VERSION 5.8 ;
BUSBITCHARS "[]" ;
DIVIDERCHAR "/" ;
UNITS
    DATABASE MICRONS 1000 ;
END UNITS

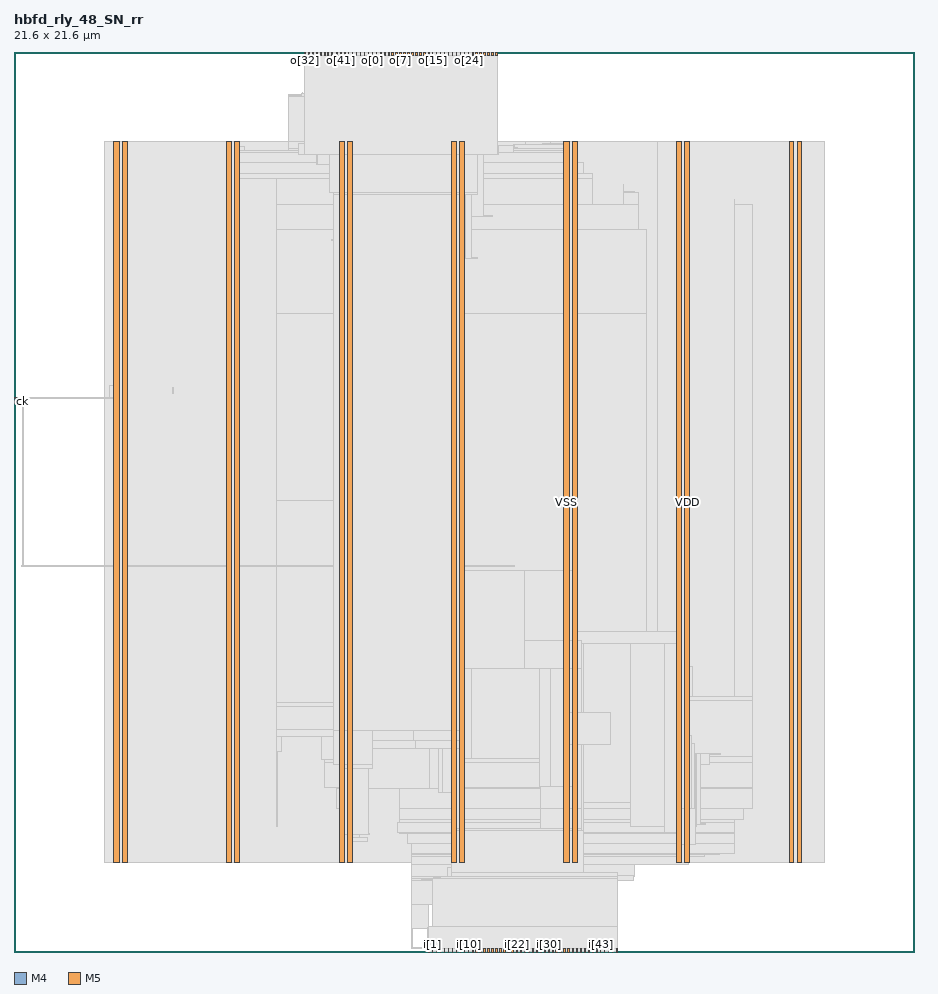
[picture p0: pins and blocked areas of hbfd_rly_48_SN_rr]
MACRO hbfd_rly_48_SN_rr
  FOREIGN hbfd_rly_48_SN_rr 0 0 ;
  CLASS BLOCK ;
  SIZE 21.6 BY 21.6 ;
  PIN ck
    DIRECTION INPUT ;
    USE SIGNAL ;
    PORT
      LAYER M4 ;
        RECT  0 13.2 0.084 13.224 ;
    END
  END ck
  PIN i[0]
    DIRECTION INPUT ;
    USE SIGNAL ;
    PORT
      LAYER M5 ;
        RECT  9.936 0 9.96 0.084 ;
    END
  END i[0]
  PIN i[10]
    DIRECTION INPUT ;
    USE SIGNAL ;
    PORT
      LAYER M5 ;
        RECT  10.896 0 10.92 0.084 ;
    END
  END i[10]
  PIN i[11]
    DIRECTION INPUT ;
    USE SIGNAL ;
    PORT
      LAYER M5 ;
        RECT  10.992 0 11.016 0.084 ;
    END
  END i[11]
  PIN i[12]
    DIRECTION INPUT ;
    USE SIGNAL ;
    PORT
      LAYER M5 ;
        RECT  11.088 0 11.112 0.084 ;
    END
  END i[12]
  PIN i[13]
    DIRECTION INPUT ;
    USE SIGNAL ;
    PORT
      LAYER M5 ;
        RECT  11.184 0 11.208 0.084 ;
    END
  END i[13]
  PIN i[14]
    DIRECTION INPUT ;
    USE SIGNAL ;
    PORT
      LAYER M5 ;
        RECT  11.28 0 11.304 0.084 ;
    END
  END i[14]
  PIN i[15]
    DIRECTION INPUT ;
    USE SIGNAL ;
    PORT
      LAYER M5 ;
        RECT  11.376 0 11.4 0.084 ;
    END
  END i[15]
  PIN i[16]
    DIRECTION INPUT ;
    USE SIGNAL ;
    PORT
      LAYER M5 ;
        RECT  11.472 0 11.496 0.084 ;
    END
  END i[16]
  PIN i[17]
    DIRECTION INPUT ;
    USE SIGNAL ;
    PORT
      LAYER M5 ;
        RECT  11.568 0 11.592 0.084 ;
    END
  END i[17]
  PIN i[18]
    DIRECTION INPUT ;
    USE SIGNAL ;
    PORT
      LAYER M5 ;
        RECT  11.664 0 11.688 0.084 ;
    END
  END i[18]
  PIN i[19]
    DIRECTION INPUT ;
    USE SIGNAL ;
    PORT
      LAYER M5 ;
        RECT  11.76 0 11.784 0.084 ;
    END
  END i[19]
  PIN i[1]
    DIRECTION INPUT ;
    USE SIGNAL ;
    PORT
      LAYER M5 ;
        RECT  10.032 0 10.056 0.084 ;
    END
  END i[1]
  PIN i[20]
    DIRECTION INPUT ;
    USE SIGNAL ;
    PORT
      LAYER M5 ;
        RECT  11.856 0 11.88 0.084 ;
    END
  END i[20]
  PIN i[21]
    DIRECTION INPUT ;
    USE SIGNAL ;
    PORT
      LAYER M5 ;
        RECT  11.952 0 11.976 0.084 ;
    END
  END i[21]
  PIN i[22]
    DIRECTION INPUT ;
    USE SIGNAL ;
    PORT
      LAYER M5 ;
        RECT  12.048 0 12.072 0.084 ;
    END
  END i[22]
  PIN i[23]
    DIRECTION INPUT ;
    USE SIGNAL ;
    PORT
      LAYER M5 ;
        RECT  12.144 0 12.168 0.084 ;
    END
  END i[23]
  PIN i[24]
    DIRECTION INPUT ;
    USE SIGNAL ;
    PORT
      LAYER M5 ;
        RECT  12.24 0 12.264 0.084 ;
    END
  END i[24]
  PIN i[25]
    DIRECTION INPUT ;
    USE SIGNAL ;
    PORT
      LAYER M5 ;
        RECT  12.336 0 12.36 0.084 ;
    END
  END i[25]
  PIN i[26]
    DIRECTION INPUT ;
    USE SIGNAL ;
    PORT
      LAYER M5 ;
        RECT  12.432 0 12.456 0.084 ;
    END
  END i[26]
  PIN i[27]
    DIRECTION INPUT ;
    USE SIGNAL ;
    PORT
      LAYER M5 ;
        RECT  12.528 0 12.552 0.084 ;
    END
  END i[27]
  PIN i[28]
    DIRECTION INPUT ;
    USE SIGNAL ;
    PORT
      LAYER M5 ;
        RECT  12.624 0 12.648 0.084 ;
    END
  END i[28]
  PIN i[29]
    DIRECTION INPUT ;
    USE SIGNAL ;
    PORT
      LAYER M5 ;
        RECT  12.72 0 12.744 0.084 ;
    END
  END i[29]
  PIN i[2]
    DIRECTION INPUT ;
    USE SIGNAL ;
    PORT
      LAYER M5 ;
        RECT  10.128 0 10.152 0.084 ;
    END
  END i[2]
  PIN i[30]
    DIRECTION INPUT ;
    USE SIGNAL ;
    PORT
      LAYER M5 ;
        RECT  12.816 0 12.84 0.084 ;
    END
  END i[30]
  PIN i[31]
    DIRECTION INPUT ;
    USE SIGNAL ;
    PORT
      LAYER M5 ;
        RECT  12.912 0 12.936 0.084 ;
    END
  END i[31]
  PIN i[32]
    DIRECTION INPUT ;
    USE SIGNAL ;
    PORT
      LAYER M5 ;
        RECT  13.008 0 13.032 0.084 ;
    END
  END i[32]
  PIN i[33]
    DIRECTION INPUT ;
    USE SIGNAL ;
    PORT
      LAYER M5 ;
        RECT  13.104 0 13.128 0.084 ;
    END
  END i[33]
  PIN i[34]
    DIRECTION INPUT ;
    USE SIGNAL ;
    PORT
      LAYER M5 ;
        RECT  13.2 0 13.224 0.084 ;
    END
  END i[34]
  PIN i[35]
    DIRECTION INPUT ;
    USE SIGNAL ;
    PORT
      LAYER M5 ;
        RECT  13.296 0 13.32 0.084 ;
    END
  END i[35]
  PIN i[36]
    DIRECTION INPUT ;
    USE SIGNAL ;
    PORT
      LAYER M5 ;
        RECT  13.392 0 13.416 0.084 ;
    END
  END i[36]
  PIN i[37]
    DIRECTION INPUT ;
    USE SIGNAL ;
    PORT
      LAYER M5 ;
        RECT  13.488 0 13.512 0.084 ;
    END
  END i[37]
  PIN i[38]
    DIRECTION INPUT ;
    USE SIGNAL ;
    PORT
      LAYER M5 ;
        RECT  13.584 0 13.608 0.084 ;
    END
  END i[38]
  PIN i[39]
    DIRECTION INPUT ;
    USE SIGNAL ;
    PORT
      LAYER M5 ;
        RECT  13.68 0 13.704 0.084 ;
    END
  END i[39]
  PIN i[3]
    DIRECTION INPUT ;
    USE SIGNAL ;
    PORT
      LAYER M5 ;
        RECT  10.224 0 10.248 0.084 ;
    END
  END i[3]
  PIN i[40]
    DIRECTION INPUT ;
    USE SIGNAL ;
    PORT
      LAYER M5 ;
        RECT  13.776 0 13.8 0.084 ;
    END
  END i[40]
  PIN i[41]
    DIRECTION INPUT ;
    USE SIGNAL ;
    PORT
      LAYER M5 ;
        RECT  13.872 0 13.896 0.084 ;
    END
  END i[41]
  PIN i[42]
    DIRECTION INPUT ;
    USE SIGNAL ;
    PORT
      LAYER M5 ;
        RECT  13.968 0 13.992 0.084 ;
    END
  END i[42]
  PIN i[43]
    DIRECTION INPUT ;
    USE SIGNAL ;
    PORT
      LAYER M5 ;
        RECT  14.064 0 14.088 0.084 ;
    END
  END i[43]
  PIN i[44]
    DIRECTION INPUT ;
    USE SIGNAL ;
    PORT
      LAYER M5 ;
        RECT  14.16 0 14.184 0.084 ;
    END
  END i[44]
  PIN i[45]
    DIRECTION INPUT ;
    USE SIGNAL ;
    PORT
      LAYER M5 ;
        RECT  14.256 0 14.28 0.084 ;
    END
  END i[45]
  PIN i[46]
    DIRECTION INPUT ;
    USE SIGNAL ;
    PORT
      LAYER M5 ;
        RECT  14.352 0 14.376 0.084 ;
    END
  END i[46]
  PIN i[47]
    DIRECTION INPUT ;
    USE SIGNAL ;
    PORT
      LAYER M5 ;
        RECT  14.448 0 14.472 0.084 ;
    END
  END i[47]
  PIN i[4]
    DIRECTION INPUT ;
    USE SIGNAL ;
    PORT
      LAYER M5 ;
        RECT  10.32 0 10.344 0.084 ;
    END
  END i[4]
  PIN i[5]
    DIRECTION INPUT ;
    USE SIGNAL ;
    PORT
      LAYER M5 ;
        RECT  10.416 0 10.44 0.084 ;
    END
  END i[5]
  PIN i[6]
    DIRECTION INPUT ;
    USE SIGNAL ;
    PORT
      LAYER M5 ;
        RECT  10.512 0 10.536 0.084 ;
    END
  END i[6]
  PIN i[7]
    DIRECTION INPUT ;
    USE SIGNAL ;
    PORT
      LAYER M5 ;
        RECT  10.608 0 10.632 0.084 ;
    END
  END i[7]
  PIN i[8]
    DIRECTION INPUT ;
    USE SIGNAL ;
    PORT
      LAYER M5 ;
        RECT  10.704 0 10.728 0.084 ;
    END
  END i[8]
  PIN i[9]
    DIRECTION INPUT ;
    USE SIGNAL ;
    PORT
      LAYER M5 ;
        RECT  10.8 0 10.824 0.084 ;
    END
  END i[9]
  PIN o[0]
    DIRECTION OUTPUT ;
    USE SIGNAL ;
    PORT
      LAYER M5 ;
        RECT  8.592 21.516 8.616 21.6 ;
    END
  END o[0]
  PIN o[10]
    DIRECTION OUTPUT ;
    USE SIGNAL ;
    PORT
      LAYER M5 ;
        RECT  9.552 21.516 9.576 21.6 ;
    END
  END o[10]
  PIN o[11]
    DIRECTION OUTPUT ;
    USE SIGNAL ;
    PORT
      LAYER M5 ;
        RECT  9.648 21.516 9.672 21.6 ;
    END
  END o[11]
  PIN o[12]
    DIRECTION OUTPUT ;
    USE SIGNAL ;
    PORT
      LAYER M5 ;
        RECT  9.744 21.516 9.768 21.6 ;
    END
  END o[12]
  PIN o[13]
    DIRECTION OUTPUT ;
    USE SIGNAL ;
    PORT
      LAYER M5 ;
        RECT  9.84 21.516 9.864 21.6 ;
    END
  END o[13]
  PIN o[14]
    DIRECTION OUTPUT ;
    USE SIGNAL ;
    PORT
      LAYER M5 ;
        RECT  9.936 21.516 9.96 21.6 ;
    END
  END o[14]
  PIN o[15]
    DIRECTION OUTPUT ;
    USE SIGNAL ;
    PORT
      LAYER M5 ;
        RECT  10.032 21.516 10.056 21.6 ;
    END
  END o[15]
  PIN o[16]
    DIRECTION OUTPUT ;
    USE SIGNAL ;
    PORT
      LAYER M5 ;
        RECT  10.128 21.516 10.152 21.6 ;
    END
  END o[16]
  PIN o[17]
    DIRECTION OUTPUT ;
    USE SIGNAL ;
    PORT
      LAYER M5 ;
        RECT  10.224 21.516 10.248 21.6 ;
    END
  END o[17]
  PIN o[18]
    DIRECTION OUTPUT ;
    USE SIGNAL ;
    PORT
      LAYER M5 ;
        RECT  10.32 21.516 10.344 21.6 ;
    END
  END o[18]
  PIN o[19]
    DIRECTION OUTPUT ;
    USE SIGNAL ;
    PORT
      LAYER M5 ;
        RECT  10.416 21.516 10.44 21.6 ;
    END
  END o[19]
  PIN o[1]
    DIRECTION OUTPUT ;
    USE SIGNAL ;
    PORT
      LAYER M5 ;
        RECT  8.688 21.516 8.712 21.6 ;
    END
  END o[1]
  PIN o[20]
    DIRECTION OUTPUT ;
    USE SIGNAL ;
    PORT
      LAYER M5 ;
        RECT  10.512 21.516 10.536 21.6 ;
    END
  END o[20]
  PIN o[21]
    DIRECTION OUTPUT ;
    USE SIGNAL ;
    PORT
      LAYER M5 ;
        RECT  10.608 21.516 10.632 21.6 ;
    END
  END o[21]
  PIN o[22]
    DIRECTION OUTPUT ;
    USE SIGNAL ;
    PORT
      LAYER M5 ;
        RECT  10.704 21.516 10.728 21.6 ;
    END
  END o[22]
  PIN o[23]
    DIRECTION OUTPUT ;
    USE SIGNAL ;
    PORT
      LAYER M5 ;
        RECT  10.8 21.516 10.824 21.6 ;
    END
  END o[23]
  PIN o[24]
    DIRECTION OUTPUT ;
    USE SIGNAL ;
    PORT
      LAYER M5 ;
        RECT  10.896 21.516 10.92 21.6 ;
    END
  END o[24]
  PIN o[25]
    DIRECTION OUTPUT ;
    USE SIGNAL ;
    PORT
      LAYER M5 ;
        RECT  10.992 21.516 11.016 21.6 ;
    END
  END o[25]
  PIN o[26]
    DIRECTION OUTPUT ;
    USE SIGNAL ;
    PORT
      LAYER M5 ;
        RECT  11.088 21.516 11.112 21.6 ;
    END
  END o[26]
  PIN o[27]
    DIRECTION OUTPUT ;
    USE SIGNAL ;
    PORT
      LAYER M5 ;
        RECT  11.184 21.516 11.208 21.6 ;
    END
  END o[27]
  PIN o[28]
    DIRECTION OUTPUT ;
    USE SIGNAL ;
    PORT
      LAYER M5 ;
        RECT  11.28 21.516 11.304 21.6 ;
    END
  END o[28]
  PIN o[29]
    DIRECTION OUTPUT ;
    USE SIGNAL ;
    PORT
      LAYER M5 ;
        RECT  11.376 21.516 11.4 21.6 ;
    END
  END o[29]
  PIN o[2]
    DIRECTION OUTPUT ;
    USE SIGNAL ;
    PORT
      LAYER M5 ;
        RECT  8.784 21.516 8.808 21.6 ;
    END
  END o[2]
  PIN o[30]
    DIRECTION OUTPUT ;
    USE SIGNAL ;
    PORT
      LAYER M5 ;
        RECT  11.472 21.516 11.496 21.6 ;
    END
  END o[30]
  PIN o[31]
    DIRECTION OUTPUT ;
    USE SIGNAL ;
    PORT
      LAYER M5 ;
        RECT  11.568 21.516 11.592 21.6 ;
    END
  END o[31]
  PIN o[32]
    DIRECTION OUTPUT ;
    USE SIGNAL ;
    PORT
      LAYER M5 ;
        RECT  6.96 21.516 6.984 21.6 ;
    END
  END o[32]
  PIN o[33]
    DIRECTION OUTPUT ;
    USE SIGNAL ;
    PORT
      LAYER M5 ;
        RECT  7.056 21.516 7.08 21.6 ;
    END
  END o[33]
  PIN o[34]
    DIRECTION OUTPUT ;
    USE SIGNAL ;
    PORT
      LAYER M5 ;
        RECT  7.152 21.516 7.176 21.6 ;
    END
  END o[34]
  PIN o[35]
    DIRECTION OUTPUT ;
    USE SIGNAL ;
    PORT
      LAYER M5 ;
        RECT  7.248 21.516 7.272 21.6 ;
    END
  END o[35]
  PIN o[36]
    DIRECTION OUTPUT ;
    USE SIGNAL ;
    PORT
      LAYER M5 ;
        RECT  7.344 21.516 7.368 21.6 ;
    END
  END o[36]
  PIN o[37]
    DIRECTION OUTPUT ;
    USE SIGNAL ;
    PORT
      LAYER M5 ;
        RECT  7.44 21.516 7.464 21.6 ;
    END
  END o[37]
  PIN o[38]
    DIRECTION OUTPUT ;
    USE SIGNAL ;
    PORT
      LAYER M5 ;
        RECT  7.536 21.516 7.56 21.6 ;
    END
  END o[38]
  PIN o[39]
    DIRECTION OUTPUT ;
    USE SIGNAL ;
    PORT
      LAYER M5 ;
        RECT  7.632 21.516 7.656 21.6 ;
    END
  END o[39]
  PIN o[3]
    DIRECTION OUTPUT ;
    USE SIGNAL ;
    PORT
      LAYER M5 ;
        RECT  8.88 21.516 8.904 21.6 ;
    END
  END o[3]
  PIN o[40]
    DIRECTION OUTPUT ;
    USE SIGNAL ;
    PORT
      LAYER M5 ;
        RECT  7.728 21.516 7.752 21.6 ;
    END
  END o[40]
  PIN o[41]
    DIRECTION OUTPUT ;
    USE SIGNAL ;
    PORT
      LAYER M5 ;
        RECT  7.824 21.516 7.848 21.6 ;
    END
  END o[41]
  PIN o[42]
    DIRECTION OUTPUT ;
    USE SIGNAL ;
    PORT
      LAYER M5 ;
        RECT  7.92 21.516 7.944 21.6 ;
    END
  END o[42]
  PIN o[43]
    DIRECTION OUTPUT ;
    USE SIGNAL ;
    PORT
      LAYER M5 ;
        RECT  8.016 21.516 8.04 21.6 ;
    END
  END o[43]
  PIN o[44]
    DIRECTION OUTPUT ;
    USE SIGNAL ;
    PORT
      LAYER M5 ;
        RECT  8.112 21.516 8.136 21.6 ;
    END
  END o[44]
  PIN o[45]
    DIRECTION OUTPUT ;
    USE SIGNAL ;
    PORT
      LAYER M5 ;
        RECT  8.208 21.516 8.232 21.6 ;
    END
  END o[45]
  PIN o[46]
    DIRECTION OUTPUT ;
    USE SIGNAL ;
    PORT
      LAYER M5 ;
        RECT  8.304 21.516 8.328 21.6 ;
    END
  END o[46]
  PIN o[47]
    DIRECTION OUTPUT ;
    USE SIGNAL ;
    PORT
      LAYER M5 ;
        RECT  8.4 21.516 8.424 21.6 ;
    END
  END o[47]
  PIN o[4]
    DIRECTION OUTPUT ;
    USE SIGNAL ;
    PORT
      LAYER M5 ;
        RECT  8.976 21.516 9 21.6 ;
    END
  END o[4]
  PIN o[5]
    DIRECTION OUTPUT ;
    USE SIGNAL ;
    PORT
      LAYER M5 ;
        RECT  9.072 21.516 9.096 21.6 ;
    END
  END o[5]
  PIN o[6]
    DIRECTION OUTPUT ;
    USE SIGNAL ;
    PORT
      LAYER M5 ;
        RECT  9.168 21.516 9.192 21.6 ;
    END
  END o[6]
  PIN o[7]
    DIRECTION OUTPUT ;
    USE SIGNAL ;
    PORT
      LAYER M5 ;
        RECT  9.264 21.516 9.288 21.6 ;
    END
  END o[7]
  PIN o[8]
    DIRECTION OUTPUT ;
    USE SIGNAL ;
    PORT
      LAYER M5 ;
        RECT  9.36 21.516 9.384 21.6 ;
    END
  END o[8]
  PIN o[9]
    DIRECTION OUTPUT ;
    USE SIGNAL ;
    PORT
      LAYER M5 ;
        RECT  9.456 21.516 9.48 21.6 ;
    END
  END o[9]
  PIN rs
    DIRECTION INPUT ;
    USE SIGNAL ;
    PORT
      LAYER M4 ;
        RECT  0 13.296 0.084 13.32 ;
    END
  END rs
  PIN rso
    DIRECTION OUTPUT ;
    USE SIGNAL ;
    PORT
      LAYER M5 ;
        RECT  8.496 21.516 8.52 21.6 ;
    END
  END rso
  PIN VDD
    DIRECTION INOUT ;
    USE POWER ;
    PORT
      LAYER M5 ;
        RECT  18.792 2.151 18.912 19.449 ;
        RECT  16.092 2.151 16.212 19.449 ;
        RECT  13.392 2.151 13.512 19.449 ;
        RECT  10.692 2.151 10.812 19.449 ;
        RECT  7.992 2.151 8.112 19.449 ;
        RECT  5.292 2.151 5.412 19.449 ;
        RECT  2.592 2.151 2.712 19.449 ;
    END
  END VDD
  PIN VSS
    DIRECTION INOUT ;
    USE GROUND ;
    PORT
      LAYER M5 ;
        RECT  18.6 2.137 18.72 19.463 ;
        RECT  15.9 2.137 16.02 19.463 ;
        RECT  13.2 2.137 13.32 19.463 ;
        RECT  10.5 2.137 10.62 19.463 ;
        RECT  7.8 2.137 7.92 19.463 ;
        RECT  5.1 2.137 5.22 19.463 ;
        RECT  2.4 2.137 2.52 19.463 ;
    END
  END VSS
  # OT_OBS_CLOSED layer=M5 d_um=1.536 added=3
  OBS
    LAYER RVTN ;
     RECT  2.16 2.16 19.44 2.295 ;
     RECT  2.16 2.565 19.44 2.835 ;
     RECT  2.16 3.105 19.44 3.375 ;
     RECT  2.16 3.645 19.44 3.915 ;
     RECT  2.16 4.185 19.44 4.455 ;
     RECT  2.16 4.725 19.44 4.995 ;
     RECT  2.16 5.265 19.44 5.535 ;
     RECT  2.16 5.805 19.44 6.075 ;
     RECT  2.16 6.345 19.44 6.615 ;
     RECT  2.16 6.885 19.44 7.155 ;
     RECT  2.16 7.425 19.44 7.695 ;
     RECT  2.16 7.965 19.44 8.235 ;
     RECT  2.16 8.505 19.44 8.775 ;
     RECT  2.16 9.045 19.44 9.315 ;
     RECT  2.16 9.585 19.44 9.855 ;
     RECT  2.16 10.125 19.44 10.395 ;
     RECT  2.16 10.665 19.44 10.935 ;
     RECT  2.16 11.205 19.44 11.475 ;
     RECT  2.16 11.745 19.44 12.015 ;
     RECT  2.16 12.285 19.44 12.555 ;
     RECT  2.16 12.825 19.44 13.095 ;
     RECT  2.16 13.365 19.44 13.635 ;
     RECT  2.16 13.905 19.44 14.175 ;
     RECT  2.16 14.445 19.44 14.715 ;
     RECT  2.16 14.985 19.44 15.255 ;
     RECT  2.16 15.525 19.44 15.795 ;
     RECT  2.16 16.065 19.44 16.335 ;
     RECT  2.16 16.605 19.44 16.875 ;
     RECT  2.16 17.145 19.44 17.415 ;
     RECT  2.16 17.685 19.44 17.955 ;
     RECT  2.16 18.225 19.44 18.495 ;
     RECT  2.16 18.765 19.44 19.035 ;
     RECT  2.16 19.305 19.44 19.44 ;
    LAYER RVTP ;
     RECT  2.16 2.295 19.44 2.565 ;
     RECT  2.16 2.835 19.44 3.105 ;
     RECT  2.16 3.375 19.44 3.645 ;
     RECT  2.16 3.915 19.44 4.185 ;
     RECT  2.16 4.455 19.44 4.725 ;
     RECT  2.16 4.995 19.44 5.265 ;
     RECT  2.16 5.535 19.44 5.805 ;
     RECT  2.16 6.075 19.44 6.345 ;
     RECT  2.16 6.615 19.44 6.885 ;
     RECT  2.16 7.155 19.44 7.425 ;
     RECT  2.16 7.695 19.44 7.965 ;
     RECT  2.16 8.235 19.44 8.505 ;
     RECT  2.16 8.775 19.44 9.045 ;
     RECT  2.16 9.315 19.44 9.585 ;
     RECT  2.16 9.855 19.44 10.125 ;
     RECT  2.16 10.395 19.44 10.665 ;
     RECT  2.16 10.935 19.44 11.205 ;
     RECT  2.16 11.475 19.44 11.745 ;
     RECT  2.16 12.015 19.44 12.285 ;
     RECT  2.16 12.555 19.44 12.825 ;
     RECT  2.16 13.095 19.44 13.365 ;
     RECT  2.16 13.635 19.44 13.905 ;
     RECT  2.16 14.175 19.44 14.445 ;
     RECT  2.16 14.715 19.44 14.985 ;
     RECT  2.16 15.255 19.44 15.525 ;
     RECT  2.16 15.795 19.44 16.065 ;
     RECT  2.16 16.335 19.44 16.605 ;
     RECT  2.16 16.875 19.44 17.145 ;
     RECT  2.16 17.415 19.44 17.685 ;
     RECT  2.16 17.955 19.44 18.225 ;
     RECT  2.16 18.495 19.44 18.765 ;
     RECT  2.16 19.035 19.44 19.305 ;
    LAYER M1 ;
     RECT  2.16 2.151 19.44 19.449 ;
    LAYER M2 ;
     RECT  2.16 2.151 12.271 19.449 ;
     RECT  12.271 2.106 12.875 19.449 ;
     RECT  12.875 2.151 15.439 19.449 ;
     RECT  15.439 2.106 16.187 19.449 ;
     RECT  16.187 2.151 19.44 19.449 ;
    LAYER M3 ;
     RECT  9.54 0.091 9.558 0.571 ;
     RECT  9.54 0.571 9.954 1.147 ;
     RECT  9.54 1.147 10.314 1.723 ;
     RECT  11.124 0.571 11.142 1.723 ;
     RECT  12.456 1.147 12.474 1.723 ;
     RECT  14.256 0.091 14.274 1.723 ;
     RECT  9.54 1.723 12.762 1.771 ;
     RECT  13.536 1.723 14.85 1.771 ;
     RECT  9.54 1.771 14.85 1.819 ;
     RECT  9.54 1.819 14.886 2.101 ;
     RECT  9.54 2.101 16.182 2.299 ;
     RECT  9.54 2.299 16.578 2.335 ;
     RECT  9.54 2.335 16.938 2.371 ;
     RECT  2.415 2.143 2.505 2.413 ;
     RECT  5.115 2.143 5.205 2.413 ;
     RECT  7.815 2.143 7.905 2.413 ;
     RECT  18.615 2.143 18.705 2.413 ;
     RECT  9.54 2.371 17.298 2.605 ;
     RECT  7.815 2.413 8.097 2.641 ;
     RECT  7.815 2.641 8.478 2.759 ;
     RECT  9.432 2.605 17.298 2.839 ;
     RECT  7.815 2.759 8.298 2.861 ;
     RECT  9.252 2.839 17.298 2.875 ;
     RECT  9.216 2.875 17.298 3.101 ;
     RECT  9.252 3.101 17.298 3.181 ;
     RECT  7.815 2.861 8.097 3.451 ;
     RECT  9.252 3.181 17.514 3.451 ;
     RECT  7.74 3.451 8.097 3.931 ;
     RECT  9.252 3.451 17.73 3.931 ;
     RECT  7.74 3.931 17.73 3.955 ;
     RECT  7.452 3.955 17.73 4.541 ;
     RECT  9.36 4.541 17.73 4.559 ;
     RECT  7.452 4.541 8.097 4.621 ;
     RECT  9.432 4.559 17.73 4.685 ;
     RECT  6.3 3.001 6.318 4.801 ;
     RECT  6.3 4.801 6.426 5.161 ;
     RECT  7.38 4.621 8.097 5.161 ;
     RECT  6.3 5.161 8.097 5.341 ;
     RECT  6.3 5.341 8.478 5.881 ;
     RECT  6.3 5.881 8.802 5.999 ;
     RECT  9.576 4.685 17.73 6.043 ;
     RECT  9.468 6.043 17.73 6.143 ;
     RECT  9.468 6.143 16.29 6.845 ;
     RECT  9.468 6.845 16.197 7.691 ;
     RECT  6.3 5.999 8.622 10.831 ;
     RECT  2.415 2.413 2.697 13.291 ;
     RECT  3.816 13.405 3.834 13.559 ;
     RECT  2.304 13.291 2.697 13.595 ;
     RECT  6.3 10.831 8.694 15.331 ;
     RECT  9.468 7.691 15.174 15.331 ;
     RECT  6.3 15.331 15.174 17.339 ;
     RECT  6.3 17.339 14.994 17.951 ;
     RECT  17.28 6.143 17.73 17.951 ;
     RECT  17.28 17.951 17.298 18.059 ;
     RECT  14.616 17.951 14.994 18.221 ;
     RECT  14.616 18.221 14.886 18.257 ;
     RECT  14.616 18.257 14.634 18.419 ;
     RECT  5.115 2.413 5.397 18.571 ;
     RECT  6.3 17.951 13.878 18.571 ;
     RECT  5.115 18.571 13.878 18.689 ;
     RECT  5.115 18.689 13.662 18.959 ;
     RECT  2.415 13.595 2.697 19.187 ;
     RECT  5.115 18.959 13.497 19.187 ;
     RECT  15.915 7.691 16.197 19.187 ;
     RECT  18.615 2.413 18.897 19.187 ;
     RECT  5.115 19.187 13.305 19.229 ;
     RECT  6.588 19.229 13.305 19.277 ;
     RECT  5.115 19.229 5.526 19.337 ;
     RECT  11.988 19.277 13.305 19.373 ;
     RECT  12.672 19.373 13.305 19.409 ;
     RECT  2.415 19.187 2.505 19.457 ;
     RECT  5.115 19.337 5.205 19.457 ;
     RECT  6.588 19.277 10.818 19.457 ;
     RECT  13.215 19.409 13.305 19.457 ;
     RECT  15.915 19.187 16.005 19.457 ;
     RECT  18.615 19.187 18.705 19.457 ;
     RECT  8.136 19.457 10.818 19.613 ;
     RECT  8.136 19.613 10.278 19.997 ;
     RECT  6.588 19.457 7.326 20.525 ;
     RECT  6.588 20.525 6.93 20.573 ;
     RECT  6.912 20.573 6.93 20.621 ;
     RECT  8.28 19.997 10.134 21.341 ;
     RECT  8.28 21.341 10.098 21.437 ;
     RECT  8.28 21.437 9.918 21.485 ;
    LAYER M4 ;
     RECT  0.084 13.2 0.227 13.224 ;
     RECT  0.06 13.224 0.227 13.296 ;
     RECT  0.084 13.296 0.227 13.32 ;
     RECT  0.181 9.264 2.408 9.288 ;
     RECT  0.227 13.296 2.408 13.32 ;
     RECT  2.408 2.148 2.512 19.452 ;
     RECT  2.512 2.418 2.704 19.182 ;
     RECT  2.704 9.264 5.108 9.288 ;
     RECT  5.108 2.148 5.212 19.452 ;
     RECT  5.212 2.418 5.404 19.182 ;
     RECT  6.577 20.544 6.901 20.568 ;
     RECT  6.829 19.152 7.117 19.416 ;
     RECT  7.117 19.152 7.261 19.56 ;
     RECT  7.261 18.912 7.282 19.56 ;
     RECT  6.901 20.544 7.282 20.616 ;
     RECT  7.282 18.912 7.573 20.616 ;
     RECT  7.573 18.24 7.763 20.616 ;
     RECT  7.669 4.512 7.808 4.536 ;
     RECT  5.404 9.264 7.808 9.288 ;
     RECT  7.729 15.456 7.808 15.48 ;
     RECT  7.621 17.088 7.808 17.112 ;
     RECT  7.763 18.24 7.808 19.992 ;
     RECT  7.808 2.148 7.912 19.992 ;
     RECT  7.912 2.418 8.104 19.992 ;
     RECT  8.104 16.464 8.147 19.992 ;
     RECT  8.104 2.832 8.531 2.856 ;
     RECT  8.147 19.872 8.533 19.992 ;
     RECT  8.005 21.456 8.945 21.48 ;
     RECT  8.147 16.464 9.173 18.84 ;
     RECT  9.173 16.512 9.245 18.84 ;
     RECT  9.245 16.56 9.349 18.84 ;
     RECT  9.349 16.56 9.596 19.032 ;
     RECT  8.945 20.496 9.596 21.48 ;
     RECT  9.596 16.56 9.641 21.48 ;
     RECT  9.529 0.096 9.925 0.12 ;
     RECT  9.641 21.312 9.929 21.48 ;
     RECT  8.104 3.936 9.973 5.352 ;
     RECT  9.925 0.096 10.009 0.6 ;
     RECT  9.781 1.728 10.066 1.752 ;
     RECT  9.929 21.312 10.109 21.432 ;
     RECT  10.109 21.312 10.145 21.336 ;
     RECT  10.009 0.096 10.163 0.12 ;
     RECT  9.973 3.936 10.177 6.12 ;
     RECT  10.066 1.728 10.285 1.8 ;
     RECT  10.177 3.84 10.285 6.12 ;
     RECT  8.104 7.2 10.285 7.224 ;
     RECT  8.104 15.456 10.285 15.48 ;
     RECT  10.285 1.152 10.369 1.8 ;
     RECT  10.369 1.728 10.393 1.8 ;
     RECT  10.393 1.728 10.508 2.04 ;
     RECT  10.285 3.84 10.508 7.224 ;
     RECT  8.104 9.264 10.508 9.288 ;
     RECT  10.285 15.456 10.508 15.576 ;
     RECT  9.641 16.56 10.508 19.992 ;
     RECT  10.508 1.728 10.547 19.992 ;
     RECT  10.547 1.728 10.804 19.608 ;
     RECT  10.804 1.728 10.835 2.952 ;
     RECT  10.804 16.656 10.835 19.608 ;
     RECT  10.804 4.656 10.973 7.224 ;
     RECT  10.835 16.656 10.973 19.368 ;
     RECT  10.973 16.656 11.117 16.68 ;
     RECT  11.113 0.576 11.219 0.6 ;
     RECT  10.973 17.664 11.261 19.368 ;
     RECT  11.261 17.664 11.477 17.688 ;
     RECT  11.261 19.152 11.621 19.368 ;
     RECT  11.621 19.2 11.981 19.368 ;
     RECT  10.804 9.264 12.017 9.288 ;
     RECT  11.981 19.296 12.017 19.368 ;
     RECT  12.017 19.296 12.089 19.32 ;
     RECT  10.835 1.728 12.373 1.8 ;
     RECT  12.373 1.728 12.445 1.848 ;
     RECT  10.973 4.656 12.613 7.128 ;
     RECT  12.445 1.152 12.755 1.848 ;
     RECT  10.835 2.88 12.869 2.952 ;
     RECT  12.613 3.936 12.869 7.128 ;
     RECT  12.869 2.88 12.877 7.128 ;
     RECT  12.755 1.728 13.189 1.848 ;
     RECT  12.877 2.88 13.189 7.416 ;
     RECT  13.189 1.728 13.208 7.416 ;
     RECT  12.229 9.12 13.208 9.144 ;
     RECT  13.208 1.728 13.312 19.452 ;
     RECT  13.381 0.336 13.429 0.36 ;
     RECT  13.312 1.728 13.504 19.182 ;
     RECT  13.429 0.144 13.619 0.36 ;
     RECT  13.504 2.88 13.619 7.464 ;
     RECT  13.619 0.144 13.667 0.264 ;
     RECT  13.619 2.88 13.667 7.416 ;
     RECT  14.245 0.096 14.329 0.12 ;
     RECT  13.504 1.728 14.483 1.896 ;
     RECT  13.667 3.6 14.785 7.416 ;
     RECT  14.483 1.728 14.861 1.848 ;
     RECT  14.861 1.824 14.897 1.848 ;
     RECT  14.785 3.024 15.613 7.416 ;
     RECT  15.613 2.88 15.908 7.416 ;
     RECT  15.908 2.148 16.012 19.452 ;
     RECT  16.012 2.418 16.204 19.182 ;
     RECT  16.204 2.592 16.265 5.208 ;
     RECT  16.265 2.592 16.337 5.016 ;
     RECT  16.337 2.592 16.355 4.776 ;
     RECT  16.355 3.024 16.373 4.776 ;
     RECT  16.373 3.072 16.481 4.776 ;
     RECT  16.481 3.072 16.589 3.096 ;
     RECT  16.481 4.512 16.697 4.776 ;
     RECT  16.697 4.752 16.949 4.776 ;
     RECT  18.608 2.148 18.712 19.452 ;
     RECT  18.712 2.418 18.904 19.182 ;
    LAYER M5 ;
     RECT  9.96 0.016 10.032 0.084 ;
     RECT  10.056 0.016 10.128 0.084 ;
     RECT  10.152 0.016 10.224 0.084 ;
     RECT  10.248 0.016 10.32 0.084 ;
     RECT  10.344 0.016 10.416 0.084 ;
     RECT  10.44 0.016 10.512 0.084 ;
     RECT  10.536 0.016 10.608 0.084 ;
     RECT  10.632 0.016 10.704 0.084 ;
     RECT  10.728 0.016 10.8 0.084 ;
     RECT  10.824 0.016 10.896 0.084 ;
     RECT  10.92 0.016 10.992 0.084 ;
     RECT  11.016 0.016 11.088 0.084 ;
     RECT  11.112 0.016 11.184 0.084 ;
     RECT  11.208 0.016 11.28 0.084 ;
     RECT  11.304 0.016 11.376 0.084 ;
     RECT  11.4 0.016 11.472 0.084 ;
     RECT  11.496 0.016 11.568 0.084 ;
     RECT  11.592 0.016 11.664 0.084 ;
     RECT  11.688 0.016 11.76 0.084 ;
     RECT  11.784 0.016 11.856 0.084 ;
     RECT  11.88 0.016 11.952 0.084 ;
     RECT  11.976 0.016 12.048 0.084 ;
     RECT  12.072 0.016 12.144 0.084 ;
     RECT  12.168 0.016 12.24 0.084 ;
     RECT  12.264 0.016 12.336 0.084 ;
     RECT  12.36 0.016 12.432 0.084 ;
     RECT  12.456 0.016 12.528 0.084 ;
     RECT  12.552 0.016 12.624 0.084 ;
     RECT  12.648 0.016 12.72 0.084 ;
     RECT  12.744 0.016 12.816 0.084 ;
     RECT  12.84 0.016 12.912 0.084 ;
     RECT  12.936 0.016 13.008 0.084 ;
     RECT  13.032 0.016 13.104 0.084 ;
     RECT  13.128 0.016 13.2 0.084 ;
     RECT  13.224 0.016 13.296 0.084 ;
     RECT  13.32 0.016 13.392 0.084 ;
     RECT  13.416 0.016 13.488 0.084 ;
     RECT  13.512 0.016 13.584 0.084 ;
     RECT  13.608 0.016 13.68 0.084 ;
     RECT  13.704 0.016 13.776 0.084 ;
     RECT  13.8 0.016 13.872 0.084 ;
     RECT  13.896 0.016 13.968 0.084 ;
     RECT  13.992 0.016 14.064 0.084 ;
     RECT  14.088 0.016 14.16 0.084 ;
     RECT  14.184 0.016 14.256 0.084 ;
     RECT  14.28 0.016 14.352 0.084 ;
     RECT  14.376 0.016 14.448 0.084 ;
     RECT  9.936 0.084 14.472 0.611 ;
     RECT  10.032 0.611 14.472 1.763 ;
     RECT  10.224 1.763 14.472 1.811 ;
     RECT  10.5 1.811 14.472 1.907 ;
     RECT  2.4 2.137 2.52 2.151 ;
     RECT  5.1 2.137 5.22 2.151 ;
     RECT  7.8 2.137 7.92 2.151 ;
     RECT  15.9 2.137 16.02 2.151 ;
     RECT  18.6 2.137 18.72 2.151 ;
     RECT  15.9 2.151 16.212 2.581 ;
     RECT  7.8 2.151 8.112 2.821 ;
     RECT  10.5 1.907 13.656 2.915 ;
     RECT  10.5 2.915 13.608 2.963 ;
     RECT  12.624 2.963 13.608 3.443 ;
     RECT  15.9 2.581 16.344 3.443 ;
     RECT  12.624 3.443 13.512 3.971 ;
     RECT  7.8 2.821 8.52 4.405 ;
     RECT  7.8 4.405 8.616 4.501 ;
     RECT  10.5 2.963 10.812 4.885 ;
     RECT  13.2 3.971 13.512 4.981 ;
     RECT  9.648 4.885 10.812 5.077 ;
     RECT  7.68 4.501 8.616 5.317 ;
     RECT  9.6 5.077 10.812 5.317 ;
     RECT  13.2 4.981 14.328 5.747 ;
     RECT  13.2 5.747 13.608 6.805 ;
     RECT  12.24 6.805 13.608 7.475 ;
     RECT  12.24 7.475 13.512 9.155 ;
     RECT  0.192 9.253 0.216 13.235 ;
     RECT  7.68 5.317 10.812 18.181 ;
     RECT  7.68 18.181 11.112 18.229 ;
     RECT  7.584 18.229 11.112 19.141 ;
     RECT  2.4 2.151 2.712 19.449 ;
     RECT  5.1 2.151 5.412 19.449 ;
     RECT  13.2 9.155 13.512 19.449 ;
     RECT  15.9 3.443 16.212 19.449 ;
     RECT  18.6 2.151 18.912 19.449 ;
     RECT  2.4 19.449 2.52 19.463 ;
     RECT  5.1 19.449 5.22 19.463 ;
     RECT  13.2 19.449 13.32 19.463 ;
     RECT  15.9 19.449 16.02 19.463 ;
     RECT  18.6 19.449 18.72 19.463 ;
     RECT  6.96 19.141 11.592 21.516 ;
     RECT  6.984 21.516 7.056 21.584 ;
     RECT  7.08 21.516 7.152 21.584 ;
     RECT  7.176 21.516 7.248 21.584 ;
     RECT  7.272 21.516 7.344 21.584 ;
     RECT  7.368 21.516 7.44 21.584 ;
     RECT  7.464 21.516 7.536 21.584 ;
     RECT  7.56 21.516 7.632 21.584 ;
     RECT  7.656 21.516 7.728 21.584 ;
     RECT  7.752 21.516 7.824 21.584 ;
     RECT  7.848 21.516 7.92 21.584 ;
     RECT  7.944 21.516 8.016 21.584 ;
     RECT  8.04 21.516 8.112 21.584 ;
     RECT  8.136 21.516 8.208 21.584 ;
     RECT  8.232 21.516 8.304 21.584 ;
     RECT  8.328 21.516 8.4 21.584 ;
     RECT  8.424 21.516 8.496 21.584 ;
     RECT  8.52 21.516 8.592 21.584 ;
     RECT  8.616 21.516 8.688 21.584 ;
     RECT  8.712 21.516 8.784 21.584 ;
     RECT  8.808 21.516 8.88 21.584 ;
     RECT  8.904 21.516 8.976 21.584 ;
     RECT  9 21.516 9.072 21.584 ;
     RECT  9.096 21.516 9.168 21.584 ;
     RECT  9.192 21.516 9.264 21.584 ;
     RECT  9.288 21.516 9.36 21.584 ;
     RECT  9.384 21.516 9.456 21.584 ;
     RECT  9.48 21.516 9.552 21.584 ;
     RECT  9.576 21.516 9.648 21.584 ;
     RECT  9.672 21.516 9.744 21.584 ;
     RECT  9.768 21.516 9.84 21.584 ;
     RECT  9.864 21.516 9.936 21.584 ;
     RECT  9.96 21.516 10.032 21.584 ;
     RECT  10.056 21.516 10.128 21.584 ;
     RECT  10.152 21.516 10.224 21.584 ;
     RECT  10.248 21.516 10.32 21.584 ;
     RECT  10.344 21.516 10.416 21.584 ;
     RECT  10.44 21.516 10.512 21.584 ;
     RECT  10.536 21.516 10.608 21.584 ;
     RECT  10.632 21.516 10.704 21.584 ;
     RECT  10.728 21.516 10.8 21.584 ;
     RECT  10.824 21.516 10.896 21.584 ;
     RECT  10.92 21.516 10.992 21.584 ;
     RECT  11.016 21.516 11.088 21.584 ;
     RECT  11.112 21.516 11.184 21.584 ;
     RECT  11.208 21.516 11.28 21.584 ;
     RECT  11.304 21.516 11.376 21.584 ;
     RECT  11.4 21.516 11.472 21.584 ;
     RECT  11.496 21.516 11.568 21.584 ;
     RECT  8.616 4.885 9.648 5.077 ;
     RECT  8.616 5.077 9.6 5.317 ;
     RECT  10.812 6.805 12.24 9.155 ;
  END
END hbfd_rly_48_SN_rr
END LIBRARY
